VERSION 5.7 ;
  NOWIREEXTENSIONATPIN ON ;
  DIVIDERCHAR "/" ;
  BUSBITCHARS "[]" ;
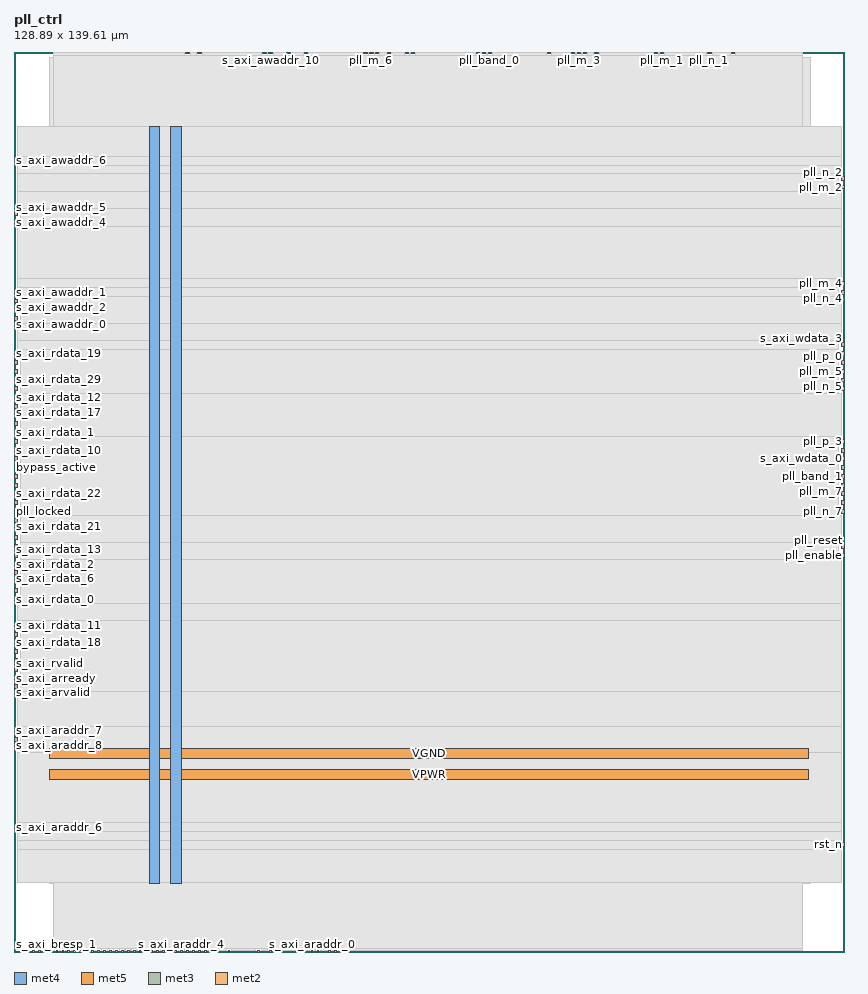
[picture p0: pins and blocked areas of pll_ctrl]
MACRO pll_ctrl
  CLASS BLOCK ;
  FOREIGN pll_ctrl ;
  ORIGIN 0.000 0.000 ;
  SIZE 128.890 BY 139.610 ;
  PIN VGND
    DIRECTION INOUT ;
    USE GROUND ;
    PORT
      LAYER met4 ;
        RECT 24.340 10.640 25.940 128.080 ;
    END
    PORT
      LAYER met5 ;
        RECT 5.520 30.030 123.280 31.630 ;
    END
  END VGND
  PIN VPWR
    DIRECTION INOUT ;
    USE POWER ;
    PORT
      LAYER met4 ;
        RECT 21.040 10.640 22.640 128.080 ;
    END
    PORT
      LAYER met5 ;
        RECT 5.520 26.730 123.280 28.330 ;
    END
  END VPWR
  PIN bypass_active
    DIRECTION OUTPUT ;
    USE SIGNAL ;
    ANTENNAGATEAREA 0.434700 ;
    ANTENNADIFFAREA 1.137600 ;
    PORT
      LAYER met3 ;
        RECT 0.000 74.840 0.600 75.440 ;
    END
  END bypass_active
  PIN pll_band_0
    DIRECTION OUTPUT ;
    USE SIGNAL ;
    ANTENNAGATEAREA 0.434700 ;
    ANTENNADIFFAREA 1.137600 ;
    PORT
      LAYER met2 ;
        RECT 73.690 139.330 73.970 139.610 ;
    END
  END pll_band_0
  PIN pll_band_1
    DIRECTION OUTPUT ;
    USE SIGNAL ;
    ANTENNAGATEAREA 0.434700 ;
    ANTENNADIFFAREA 1.137600 ;
    PORT
      LAYER met3 ;
        RECT 128.290 73.480 128.890 74.080 ;
    END
  END pll_band_1
  PIN pll_enable
    DIRECTION OUTPUT ;
    USE SIGNAL ;
    ANTENNAGATEAREA 0.434700 ;
    ANTENNADIFFAREA 1.137600 ;
    PORT
      LAYER met3 ;
        RECT 128.290 61.240 128.890 61.840 ;
    END
  END pll_enable
  PIN pll_lock_raw
    DIRECTION INPUT ;
    USE SIGNAL ;
    PORT
      LAYER met2 ;
        RECT 1.930 0.000 2.210 0.280 ;
    END
  END pll_lock_raw
  PIN pll_locked
    DIRECTION OUTPUT ;
    USE SIGNAL ;
    ANTENNAGATEAREA 0.434700 ;
    ANTENNADIFFAREA 1.137600 ;
    PORT
      LAYER met3 ;
        RECT 0.000 68.040 0.600 68.640 ;
    END
  END pll_locked
  PIN pll_m_0
    DIRECTION OUTPUT ;
    USE SIGNAL ;
    ANTENNAGATEAREA 0.434700 ;
    ANTENNADIFFAREA 1.137600 ;
    PORT
      LAYER met2 ;
        RECT 72.770 139.330 73.050 139.610 ;
    END
  END pll_m_0
  PIN pll_m_1
    DIRECTION OUTPUT ;
    USE SIGNAL ;
    ANTENNAGATEAREA 0.434700 ;
    ANTENNADIFFAREA 1.137600 ;
    PORT
      LAYER met2 ;
        RECT 100.370 139.330 100.650 139.610 ;
    END
  END pll_m_1
  PIN pll_m_2
    DIRECTION OUTPUT ;
    USE SIGNAL ;
    ANTENNAGATEAREA 0.434700 ;
    ANTENNADIFFAREA 1.137600 ;
    PORT
      LAYER met3 ;
        RECT 128.290 118.360 128.890 118.960 ;
    END
  END pll_m_2
  PIN pll_m_3
    DIRECTION OUTPUT ;
    USE SIGNAL ;
    ANTENNAGATEAREA 0.434700 ;
    ANTENNADIFFAREA 1.137600 ;
    PORT
      LAYER met2 ;
        RECT 87.490 139.330 87.770 139.610 ;
    END
  END pll_m_3
  PIN pll_m_4
    DIRECTION OUTPUT ;
    USE SIGNAL ;
    ANTENNAGATEAREA 0.434700 ;
    ANTENNADIFFAREA 1.137600 ;
    PORT
      LAYER met3 ;
        RECT 128.290 103.400 128.890 104.000 ;
    END
  END pll_m_4
  PIN pll_m_5
    DIRECTION OUTPUT ;
    USE SIGNAL ;
    ANTENNAGATEAREA 0.434700 ;
    ANTENNADIFFAREA 1.137600 ;
    PORT
      LAYER met3 ;
        RECT 128.290 89.800 128.890 90.400 ;
    END
  END pll_m_5
  PIN pll_m_6
    DIRECTION OUTPUT ;
    USE SIGNAL ;
    ANTENNAGATEAREA 0.434700 ;
    ANTENNADIFFAREA 1.137600 ;
    PORT
      LAYER met2 ;
        RECT 55.290 139.330 55.570 139.610 ;
    END
  END pll_m_6
  PIN pll_m_7
    DIRECTION OUTPUT ;
    USE SIGNAL ;
    ANTENNAGATEAREA 0.434700 ;
    ANTENNADIFFAREA 1.137600 ;
    PORT
      LAYER met3 ;
        RECT 128.290 72.120 128.890 72.720 ;
    END
  END pll_m_7
  PIN pll_n_0
    DIRECTION OUTPUT ;
    USE SIGNAL ;
    ANTENNAGATEAREA 0.434700 ;
    ANTENNADIFFAREA 1.137600 ;
    PORT
      LAYER met2 ;
        RECT 71.850 139.330 72.130 139.610 ;
    END
  END pll_n_0
  PIN pll_n_1
    DIRECTION OUTPUT ;
    USE SIGNAL ;
    ANTENNAGATEAREA 0.434700 ;
    ANTENNADIFFAREA 1.137600 ;
    PORT
      LAYER met2 ;
        RECT 107.730 139.330 108.010 139.610 ;
    END
  END pll_n_1
  PIN pll_n_2
    DIRECTION OUTPUT ;
    USE SIGNAL ;
    ANTENNAGATEAREA 0.434700 ;
    ANTENNADIFFAREA 1.137600 ;
    PORT
      LAYER met3 ;
        RECT 128.290 119.720 128.890 120.320 ;
    END
  END pll_n_2
  PIN pll_n_3
    DIRECTION OUTPUT ;
    USE SIGNAL ;
    ANTENNAGATEAREA 0.434700 ;
    ANTENNADIFFAREA 1.137600 ;
    PORT
      LAYER met2 ;
        RECT 82.890 139.330 83.170 139.610 ;
    END
  END pll_n_3
  PIN pll_n_4
    DIRECTION OUTPUT ;
    USE SIGNAL ;
    ANTENNAGATEAREA 0.434700 ;
    ANTENNADIFFAREA 1.137600 ;
    PORT
      LAYER met3 ;
        RECT 128.290 102.040 128.890 102.640 ;
    END
  END pll_n_4
  PIN pll_n_5
    DIRECTION OUTPUT ;
    USE SIGNAL ;
    ANTENNAGATEAREA 0.434700 ;
    ANTENNADIFFAREA 1.137600 ;
    PORT
      LAYER met3 ;
        RECT 128.290 88.440 128.890 89.040 ;
    END
  END pll_n_5
  PIN pll_n_6
    DIRECTION OUTPUT ;
    USE SIGNAL ;
    ANTENNAGATEAREA 0.434700 ;
    ANTENNADIFFAREA 1.137600 ;
    PORT
      LAYER met2 ;
        RECT 54.370 139.330 54.650 139.610 ;
    END
  END pll_n_6
  PIN pll_n_7
    DIRECTION OUTPUT ;
    USE SIGNAL ;
    ANTENNAGATEAREA 0.434700 ;
    ANTENNADIFFAREA 1.137600 ;
    PORT
      LAYER met3 ;
        RECT 128.290 68.040 128.890 68.640 ;
    END
  END pll_n_7
  PIN pll_p_0
    DIRECTION OUTPUT ;
    USE SIGNAL ;
    ANTENNAGATEAREA 0.434700 ;
    ANTENNADIFFAREA 1.137600 ;
    PORT
      LAYER met3 ;
        RECT 128.290 91.160 128.890 91.760 ;
    END
  END pll_p_0
  PIN pll_p_1
    DIRECTION OUTPUT ;
    USE SIGNAL ;
    ANTENNAGATEAREA 0.434700 ;
    ANTENNADIFFAREA 1.137600 ;
    PORT
      LAYER met3 ;
        RECT 128.290 87.080 128.890 87.680 ;
    END
  END pll_p_1
  PIN pll_p_2
    DIRECTION OUTPUT ;
    USE SIGNAL ;
    ANTENNAGATEAREA 0.434700 ;
    ANTENNADIFFAREA 1.137600 ;
    PORT
      LAYER met2 ;
        RECT 61.730 139.330 62.010 139.610 ;
    END
  END pll_p_2
  PIN pll_p_3
    DIRECTION OUTPUT ;
    USE SIGNAL ;
    ANTENNAGATEAREA 0.434700 ;
    ANTENNADIFFAREA 1.137600 ;
    PORT
      LAYER met3 ;
        RECT 128.290 78.920 128.890 79.520 ;
    END
  END pll_p_3
  PIN pll_reset
    DIRECTION OUTPUT ;
    USE SIGNAL ;
    ANTENNAGATEAREA 0.434700 ;
    ANTENNADIFFAREA 1.137600 ;
    PORT
      LAYER met3 ;
        RECT 128.290 62.600 128.890 63.200 ;
    END
  END pll_reset
  PIN rst_n
    DIRECTION INPUT ;
    USE SIGNAL ;
    ANTENNAGATEAREA 0.647700 ;
    ANTENNADIFFAREA 0.434700 ;
    PORT
      LAYER met3 ;
        RECT 128.290 16.360 128.890 16.960 ;
    END
  END rst_n
  PIN s_axi_araddr_0
    DIRECTION INPUT ;
    USE SIGNAL ;
    ANTENNAGATEAREA 0.647700 ;
    ANTENNADIFFAREA 0.434700 ;
    PORT
      LAYER met2 ;
        RECT 46.090 0.000 46.370 0.280 ;
    END
  END s_axi_araddr_0
  PIN s_axi_araddr_1
    DIRECTION INPUT ;
    USE SIGNAL ;
    ANTENNAGATEAREA 0.647700 ;
    ANTENNADIFFAREA 0.434700 ;
    PORT
      LAYER met2 ;
        RECT 48.850 0.000 49.130 0.280 ;
    END
  END s_axi_araddr_1
  PIN s_axi_araddr_10
    DIRECTION INPUT ;
    USE SIGNAL ;
    ANTENNAGATEAREA 0.647700 ;
    ANTENNADIFFAREA 0.434700 ;
    PORT
      LAYER met2 ;
        RECT 37.810 0.000 38.090 0.280 ;
    END
  END s_axi_araddr_10
  PIN s_axi_araddr_11
    DIRECTION INPUT ;
    USE SIGNAL ;
    ANTENNAGATEAREA 0.647700 ;
    ANTENNADIFFAREA 0.434700 ;
    PORT
      LAYER met2 ;
        RECT 47.010 0.000 47.290 0.280 ;
    END
  END s_axi_araddr_11
  PIN s_axi_araddr_2
    DIRECTION INPUT ;
    USE SIGNAL ;
    ANTENNAGATEAREA 0.647700 ;
    ANTENNADIFFAREA 0.434700 ;
    PORT
      LAYER met2 ;
        RECT 39.650 0.000 39.930 0.280 ;
    END
  END s_axi_araddr_2
  PIN s_axi_araddr_3
    DIRECTION INPUT ;
    USE SIGNAL ;
    ANTENNAGATEAREA 0.647700 ;
    ANTENNADIFFAREA 0.434700 ;
    PORT
      LAYER met2 ;
        RECT 33.210 0.000 33.490 0.280 ;
    END
  END s_axi_araddr_3
  PIN s_axi_araddr_4
    DIRECTION INPUT ;
    USE SIGNAL ;
    ANTENNAGATEAREA 0.647700 ;
    ANTENNADIFFAREA 0.434700 ;
    PORT
      LAYER met2 ;
        RECT 25.850 0.000 26.130 0.280 ;
    END
  END s_axi_araddr_4
  PIN s_axi_araddr_5
    DIRECTION INPUT ;
    USE SIGNAL ;
    ANTENNAGATEAREA 0.647700 ;
    ANTENNADIFFAREA 0.434700 ;
    PORT
      LAYER met2 ;
        RECT 18.490 0.000 18.770 0.280 ;
    END
  END s_axi_araddr_5
  PIN s_axi_araddr_6
    DIRECTION INPUT ;
    USE SIGNAL ;
    ANTENNAGATEAREA 0.647700 ;
    ANTENNADIFFAREA 0.434700 ;
    PORT
      LAYER met3 ;
        RECT 0.000 19.080 0.600 19.680 ;
    END
  END s_axi_araddr_6
  PIN s_axi_araddr_7
    DIRECTION INPUT ;
    USE SIGNAL ;
    ANTENNAGATEAREA 0.647700 ;
    ANTENNADIFFAREA 0.434700 ;
    PORT
      LAYER met3 ;
        RECT 0.000 34.040 0.600 34.640 ;
    END
  END s_axi_araddr_7
  PIN s_axi_araddr_8
    DIRECTION INPUT ;
    USE SIGNAL ;
    ANTENNAGATEAREA 0.647700 ;
    ANTENNADIFFAREA 0.434700 ;
    PORT
      LAYER met3 ;
        RECT 0.000 32.680 0.600 33.280 ;
    END
  END s_axi_araddr_8
  PIN s_axi_araddr_9
    DIRECTION INPUT ;
    USE SIGNAL ;
    ANTENNAGATEAREA 0.647700 ;
    ANTENNADIFFAREA 0.434700 ;
    PORT
      LAYER met3 ;
        RECT 0.000 31.320 0.600 31.920 ;
    END
  END s_axi_araddr_9
  PIN s_axi_arready
    DIRECTION OUTPUT ;
    USE SIGNAL ;
    ANTENNAGATEAREA 0.434700 ;
    ANTENNADIFFAREA 1.137600 ;
    PORT
      LAYER met3 ;
        RECT 0.000 42.200 0.600 42.800 ;
    END
  END s_axi_arready
  PIN s_axi_arvalid
    DIRECTION INPUT ;
    USE SIGNAL ;
    ANTENNAGATEAREA 0.647700 ;
    ANTENNADIFFAREA 0.434700 ;
    PORT
      LAYER met3 ;
        RECT 0.000 40.840 0.600 41.440 ;
    END
  END s_axi_arvalid
  PIN s_axi_awaddr_0
    DIRECTION INPUT ;
    USE SIGNAL ;
    ANTENNAGATEAREA 0.647700 ;
    ANTENNADIFFAREA 0.434700 ;
    PORT
      LAYER met3 ;
        RECT 0.000 97.960 0.600 98.560 ;
    END
  END s_axi_awaddr_0
  PIN s_axi_awaddr_1
    DIRECTION INPUT ;
    USE SIGNAL ;
    ANTENNAGATEAREA 0.647700 ;
    ANTENNADIFFAREA 0.434700 ;
    PORT
      LAYER met3 ;
        RECT 0.000 102.040 0.600 102.640 ;
    END
  END s_axi_awaddr_1
  PIN s_axi_awaddr_10
    DIRECTION INPUT ;
    USE SIGNAL ;
    ANTENNAGATEAREA 0.647700 ;
    ANTENNADIFFAREA 0.434700 ;
    PORT
      LAYER met2 ;
        RECT 39.650 139.330 39.930 139.610 ;
    END
  END s_axi_awaddr_10
  PIN s_axi_awaddr_11
    DIRECTION INPUT ;
    USE SIGNAL ;
    ANTENNAGATEAREA 0.647700 ;
    ANTENNADIFFAREA 0.434700 ;
    PORT
      LAYER met2 ;
        RECT 42.410 139.330 42.690 139.610 ;
    END
  END s_axi_awaddr_11
  PIN s_axi_awaddr_2
    DIRECTION INPUT ;
    USE SIGNAL ;
    ANTENNAGATEAREA 0.647700 ;
    ANTENNADIFFAREA 0.434700 ;
    PORT
      LAYER met3 ;
        RECT 0.000 100.680 0.600 101.280 ;
    END
  END s_axi_awaddr_2
  PIN s_axi_awaddr_3
    DIRECTION INPUT ;
    USE SIGNAL ;
    ANTENNAGATEAREA 0.647700 ;
    ANTENNADIFFAREA 0.434700 ;
    PORT
      LAYER met3 ;
        RECT 0.000 99.320 0.600 99.920 ;
    END
  END s_axi_awaddr_3
  PIN s_axi_awaddr_4
    DIRECTION INPUT ;
    USE SIGNAL ;
    ANTENNAGATEAREA 0.647700 ;
    ANTENNADIFFAREA 0.434700 ;
    PORT
      LAYER met3 ;
        RECT 0.000 112.920 0.600 113.520 ;
    END
  END s_axi_awaddr_4
  PIN s_axi_awaddr_5
    DIRECTION INPUT ;
    USE SIGNAL ;
    ANTENNAGATEAREA 0.647700 ;
    ANTENNADIFFAREA 0.434700 ;
    PORT
      LAYER met3 ;
        RECT 0.000 114.280 0.600 114.880 ;
    END
  END s_axi_awaddr_5
  PIN s_axi_awaddr_6
    DIRECTION INPUT ;
    USE SIGNAL ;
    ANTENNAGATEAREA 0.647700 ;
    ANTENNADIFFAREA 0.434700 ;
    PORT
      LAYER met3 ;
        RECT 0.000 122.440 0.600 123.040 ;
    END
  END s_axi_awaddr_6
  PIN s_axi_awaddr_7
    DIRECTION INPUT ;
    USE SIGNAL ;
    ANTENNAGATEAREA 0.647700 ;
    ANTENNADIFFAREA 0.434700 ;
    PORT
      LAYER met2 ;
        RECT 26.770 139.330 27.050 139.610 ;
    END
  END s_axi_awaddr_7
  PIN s_axi_awaddr_8
    DIRECTION INPUT ;
    USE SIGNAL ;
    ANTENNAGATEAREA 0.647700 ;
    ANTENNADIFFAREA 0.434700 ;
    PORT
      LAYER met2 ;
        RECT 28.610 139.330 28.890 139.610 ;
    END
  END s_axi_awaddr_8
  PIN s_axi_awaddr_9
    DIRECTION INPUT ;
    USE SIGNAL ;
    ANTENNAGATEAREA 0.647700 ;
    ANTENNADIFFAREA 0.434700 ;
    PORT
      LAYER met2 ;
        RECT 38.730 139.330 39.010 139.610 ;
    END
  END s_axi_awaddr_9
  PIN s_axi_awready
    DIRECTION OUTPUT ;
    USE SIGNAL ;
    ANTENNAGATEAREA 0.434700 ;
    ANTENNADIFFAREA 1.137600 ;
    PORT
      LAYER met2 ;
        RECT 45.170 139.330 45.450 139.610 ;
    END
  END s_axi_awready
  PIN s_axi_awvalid
    DIRECTION INPUT ;
    USE SIGNAL ;
    ANTENNAGATEAREA 0.647700 ;
    ANTENNADIFFAREA 0.434700 ;
    PORT
      LAYER met2 ;
        RECT 56.210 139.330 56.490 139.610 ;
    END
  END s_axi_awvalid
  PIN s_axi_bready
    DIRECTION INPUT ;
    USE SIGNAL ;
    PORT
      LAYER met2 ;
        RECT 2.850 0.000 3.130 0.280 ;
    END
  END s_axi_bready
  PIN s_axi_bresp_0
    DIRECTION OUTPUT ;
    USE SIGNAL ;
    PORT
      LAYER met2 ;
        RECT 3.770 0.000 4.050 0.280 ;
    END
  END s_axi_bresp_0
  PIN s_axi_bresp_1
    DIRECTION OUTPUT ;
    USE SIGNAL ;
    PORT
      LAYER met2 ;
        RECT 4.690 0.000 4.970 0.280 ;
    END
  END s_axi_bresp_1
  PIN s_axi_bvalid
    DIRECTION OUTPUT ;
    USE SIGNAL ;
    PORT
      LAYER met2 ;
        RECT 5.610 0.000 5.890 0.280 ;
    END
  END s_axi_bvalid
  PIN s_axi_rdata_0
    DIRECTION OUTPUT ;
    USE SIGNAL ;
    ANTENNAGATEAREA 0.434700 ;
    ANTENNADIFFAREA 1.137600 ;
    PORT
      LAYER met3 ;
        RECT 0.000 54.440 0.600 55.040 ;
    END
  END s_axi_rdata_0
  PIN s_axi_rdata_1
    DIRECTION OUTPUT ;
    USE SIGNAL ;
    ANTENNAGATEAREA 0.434700 ;
    ANTENNADIFFAREA 1.137600 ;
    PORT
      LAYER met3 ;
        RECT 0.000 80.280 0.600 80.880 ;
    END
  END s_axi_rdata_1
  PIN s_axi_rdata_10
    DIRECTION OUTPUT ;
    USE SIGNAL ;
    ANTENNAGATEAREA 0.434700 ;
    ANTENNADIFFAREA 1.137600 ;
    PORT
      LAYER met3 ;
        RECT 0.000 77.560 0.600 78.160 ;
    END
  END s_axi_rdata_10
  PIN s_axi_rdata_11
    DIRECTION OUTPUT ;
    USE SIGNAL ;
    ANTENNAGATEAREA 0.434700 ;
    ANTENNADIFFAREA 1.137600 ;
    PORT
      LAYER met3 ;
        RECT 0.000 50.360 0.600 50.960 ;
    END
  END s_axi_rdata_11
  PIN s_axi_rdata_12
    DIRECTION OUTPUT ;
    USE SIGNAL ;
    ANTENNAGATEAREA 0.434700 ;
    ANTENNADIFFAREA 1.137600 ;
    PORT
      LAYER met3 ;
        RECT 0.000 85.720 0.600 86.320 ;
    END
  END s_axi_rdata_12
  PIN s_axi_rdata_13
    DIRECTION OUTPUT ;
    USE SIGNAL ;
    ANTENNAGATEAREA 0.434700 ;
    ANTENNADIFFAREA 1.137600 ;
    PORT
      LAYER met3 ;
        RECT 0.000 61.240 0.600 61.840 ;
    END
  END s_axi_rdata_13
  PIN s_axi_rdata_14
    DIRECTION OUTPUT ;
    USE SIGNAL ;
    ANTENNAGATEAREA 0.434700 ;
    ANTENNADIFFAREA 1.137600 ;
    PORT
      LAYER met3 ;
        RECT 0.000 55.800 0.600 56.400 ;
    END
  END s_axi_rdata_14
  PIN s_axi_rdata_15
    DIRECTION OUTPUT ;
    USE SIGNAL ;
    ANTENNAGATEAREA 0.434700 ;
    ANTENNADIFFAREA 1.137600 ;
    PORT
      LAYER met3 ;
        RECT 0.000 65.320 0.600 65.920 ;
    END
  END s_axi_rdata_15
  PIN s_axi_rdata_16
    DIRECTION OUTPUT ;
    USE SIGNAL ;
    ANTENNAGATEAREA 0.434700 ;
    ANTENNADIFFAREA 1.137600 ;
    PORT
      LAYER met2 ;
        RECT 49.770 0.000 50.050 0.280 ;
    END
  END s_axi_rdata_16
  PIN s_axi_rdata_17
    DIRECTION OUTPUT ;
    USE SIGNAL ;
    ANTENNAGATEAREA 0.434700 ;
    ANTENNADIFFAREA 1.137600 ;
    PORT
      LAYER met3 ;
        RECT 0.000 84.360 0.600 84.960 ;
    END
  END s_axi_rdata_17
  PIN s_axi_rdata_18
    DIRECTION OUTPUT ;
    USE SIGNAL ;
    ANTENNAGATEAREA 0.434700 ;
    ANTENNADIFFAREA 1.137600 ;
    PORT
      LAYER met3 ;
        RECT 0.000 47.640 0.600 48.240 ;
    END
  END s_axi_rdata_18
  PIN s_axi_rdata_19
    DIRECTION OUTPUT ;
    USE SIGNAL ;
    ANTENNAGATEAREA 0.434700 ;
    ANTENNADIFFAREA 1.137600 ;
    PORT
      LAYER met3 ;
        RECT 0.000 92.520 0.600 93.120 ;
    END
  END s_axi_rdata_19
  PIN s_axi_rdata_2
    DIRECTION OUTPUT ;
    USE SIGNAL ;
    ANTENNAGATEAREA 0.434700 ;
    ANTENNADIFFAREA 1.137600 ;
    PORT
      LAYER met3 ;
        RECT 0.000 59.880 0.600 60.480 ;
    END
  END s_axi_rdata_2
  PIN s_axi_rdata_20
    DIRECTION OUTPUT ;
    USE SIGNAL ;
    ANTENNAGATEAREA 0.434700 ;
    ANTENNADIFFAREA 1.137600 ;
    PORT
      LAYER met3 ;
        RECT 0.000 76.200 0.600 76.800 ;
    END
  END s_axi_rdata_20
  PIN s_axi_rdata_21
    DIRECTION OUTPUT ;
    USE SIGNAL ;
    ANTENNAGATEAREA 0.434700 ;
    ANTENNADIFFAREA 1.137600 ;
    PORT
      LAYER met3 ;
        RECT 0.000 66.680 0.600 67.280 ;
    END
  END s_axi_rdata_21
  PIN s_axi_rdata_22
    DIRECTION OUTPUT ;
    USE SIGNAL ;
    ANTENNAGATEAREA 0.434700 ;
    ANTENNADIFFAREA 1.137600 ;
    PORT
      LAYER met3 ;
        RECT 0.000 70.760 0.600 71.360 ;
    END
  END s_axi_rdata_22
  PIN s_axi_rdata_23
    DIRECTION OUTPUT ;
    USE SIGNAL ;
    ANTENNAGATEAREA 0.434700 ;
    ANTENNADIFFAREA 1.137600 ;
    PORT
      LAYER met2 ;
        RECT 44.250 0.000 44.530 0.280 ;
    END
  END s_axi_rdata_23
  PIN s_axi_rdata_24
    DIRECTION OUTPUT ;
    USE SIGNAL ;
    ANTENNAGATEAREA 0.434700 ;
    ANTENNADIFFAREA 1.137600 ;
    PORT
      LAYER met3 ;
        RECT 0.000 63.960 0.600 64.560 ;
    END
  END s_axi_rdata_24
  PIN s_axi_rdata_25
    DIRECTION OUTPUT ;
    USE SIGNAL ;
    ANTENNAGATEAREA 0.434700 ;
    ANTENNADIFFAREA 1.137600 ;
    PORT
      LAYER met3 ;
        RECT 0.000 44.920 0.600 45.520 ;
    END
  END s_axi_rdata_25
  PIN s_axi_rdata_26
    DIRECTION OUTPUT ;
    USE SIGNAL ;
    ANTENNAGATEAREA 0.434700 ;
    ANTENNADIFFAREA 1.137600 ;
    PORT
      LAYER met3 ;
        RECT 0.000 81.640 0.600 82.240 ;
    END
  END s_axi_rdata_26
  PIN s_axi_rdata_27
    DIRECTION OUTPUT ;
    USE SIGNAL ;
    ANTENNAGATEAREA 0.434700 ;
    ANTENNADIFFAREA 1.137600 ;
    PORT
      LAYER met3 ;
        RECT 0.000 83.000 0.600 83.600 ;
    END
  END s_axi_rdata_27
  PIN s_axi_rdata_28
    DIRECTION OUTPUT ;
    USE SIGNAL ;
    ANTENNAGATEAREA 0.434700 ;
    ANTENNADIFFAREA 1.137600 ;
    PORT
      LAYER met2 ;
        RECT 50.690 0.000 50.970 0.280 ;
    END
  END s_axi_rdata_28
  PIN s_axi_rdata_29
    DIRECTION OUTPUT ;
    USE SIGNAL ;
    ANTENNAGATEAREA 0.434700 ;
    ANTENNADIFFAREA 1.137600 ;
    PORT
      LAYER met3 ;
        RECT 0.000 88.440 0.600 89.040 ;
    END
  END s_axi_rdata_29
  PIN s_axi_rdata_3
    DIRECTION OUTPUT ;
    USE SIGNAL ;
    ANTENNAGATEAREA 0.434700 ;
    ANTENNADIFFAREA 1.137600 ;
    PORT
      LAYER met3 ;
        RECT 0.000 72.120 0.600 72.720 ;
    END
  END s_axi_rdata_3
  PIN s_axi_rdata_30
    DIRECTION OUTPUT ;
    USE SIGNAL ;
    ANTENNAGATEAREA 0.434700 ;
    ANTENNADIFFAREA 1.137600 ;
    PORT
      LAYER met3 ;
        RECT 0.000 49.000 0.600 49.600 ;
    END
  END s_axi_rdata_30
  PIN s_axi_rdata_31
    DIRECTION OUTPUT ;
    USE SIGNAL ;
    ANTENNAGATEAREA 0.434700 ;
    ANTENNADIFFAREA 1.137600 ;
    PORT
      LAYER met3 ;
        RECT 0.000 62.600 0.600 63.200 ;
    END
  END s_axi_rdata_31
  PIN s_axi_rdata_4
    DIRECTION OUTPUT ;
    USE SIGNAL ;
    ANTENNAGATEAREA 0.434700 ;
    ANTENNADIFFAREA 1.137600 ;
    PORT
      LAYER met3 ;
        RECT 0.000 69.400 0.600 70.000 ;
    END
  END s_axi_rdata_4
  PIN s_axi_rdata_5
    DIRECTION OUTPUT ;
    USE SIGNAL ;
    ANTENNAGATEAREA 0.434700 ;
    ANTENNADIFFAREA 1.137600 ;
    PORT
      LAYER met3 ;
        RECT 0.000 57.160 0.600 57.760 ;
    END
  END s_axi_rdata_5
  PIN s_axi_rdata_6
    DIRECTION OUTPUT ;
    USE SIGNAL ;
    ANTENNAGATEAREA 0.434700 ;
    ANTENNADIFFAREA 1.137600 ;
    PORT
      LAYER met3 ;
        RECT 0.000 58.520 0.600 59.120 ;
    END
  END s_axi_rdata_6
  PIN s_axi_rdata_7
    DIRECTION OUTPUT ;
    USE SIGNAL ;
    ANTENNAGATEAREA 0.434700 ;
    ANTENNADIFFAREA 1.137600 ;
    PORT
      LAYER met3 ;
        RECT 0.000 91.160 0.600 91.760 ;
    END
  END s_axi_rdata_7
  PIN s_axi_rdata_8
    DIRECTION OUTPUT ;
    USE SIGNAL ;
    ANTENNAGATEAREA 0.434700 ;
    ANTENNADIFFAREA 1.137600 ;
    PORT
      LAYER met3 ;
        RECT 0.000 89.800 0.600 90.400 ;
    END
  END s_axi_rdata_8
  PIN s_axi_rdata_9
    DIRECTION OUTPUT ;
    USE SIGNAL ;
    ANTENNAGATEAREA 0.434700 ;
    ANTENNADIFFAREA 1.137600 ;
    PORT
      LAYER met3 ;
        RECT 0.000 73.480 0.600 74.080 ;
    END
  END s_axi_rdata_9
  PIN s_axi_rready
    DIRECTION INPUT ;
    USE SIGNAL ;
    ANTENNAGATEAREA 0.647700 ;
    ANTENNADIFFAREA 0.434700 ;
    PORT
      LAYER met3 ;
        RECT 0.000 46.280 0.600 46.880 ;
    END
  END s_axi_rready
  PIN s_axi_rresp_0
    DIRECTION OUTPUT ;
    USE SIGNAL ;
    ANTENNAGATEAREA 0.434700 ;
    ANTENNADIFFAREA 1.137600 ;
    PORT
      LAYER met3 ;
        RECT 0.000 87.080 0.600 87.680 ;
    END
  END s_axi_rresp_0
  PIN s_axi_rresp_1
    DIRECTION OUTPUT ;
    USE SIGNAL ;
    ANTENNAGATEAREA 0.434700 ;
    ANTENNADIFFAREA 1.137600 ;
    PORT
      LAYER met3 ;
        RECT 0.000 78.920 0.600 79.520 ;
    END
  END s_axi_rresp_1
  PIN s_axi_rvalid
    DIRECTION OUTPUT ;
    USE SIGNAL ;
    ANTENNAGATEAREA 0.434700 ;
    ANTENNADIFFAREA 1.137600 ;
    PORT
      LAYER met3 ;
        RECT 0.000 43.560 0.600 44.160 ;
    END
  END s_axi_rvalid
  PIN s_axi_wdata_0
    DIRECTION INPUT ;
    USE SIGNAL ;
    ANTENNAGATEAREA 0.647700 ;
    ANTENNADIFFAREA 0.434700 ;
    PORT
      LAYER met3 ;
        RECT 128.290 76.200 128.890 76.800 ;
    END
  END s_axi_wdata_0
  PIN s_axi_wdata_1
    DIRECTION INPUT ;
    USE SIGNAL ;
    ANTENNAGATEAREA 0.647700 ;
    ANTENNADIFFAREA 0.434700 ;
    PORT
      LAYER met2 ;
        RECT 90.250 139.330 90.530 139.610 ;
    END
  END s_axi_wdata_1
  PIN s_axi_wdata_10
    DIRECTION INPUT ;
    USE SIGNAL ;
    PORT
      LAYER met2 ;
        RECT 6.530 0.000 6.810 0.280 ;
    END
  END s_axi_wdata_10
  PIN s_axi_wdata_11
    DIRECTION INPUT ;
    USE SIGNAL ;
    PORT
      LAYER met2 ;
        RECT 7.450 0.000 7.730 0.280 ;
    END
  END s_axi_wdata_11
  PIN s_axi_wdata_12
    DIRECTION INPUT ;
    USE SIGNAL ;
    PORT
      LAYER met2 ;
        RECT 8.370 0.000 8.650 0.280 ;
    END
  END s_axi_wdata_12
  PIN s_axi_wdata_13
    DIRECTION INPUT ;
    USE SIGNAL ;
    PORT
      LAYER met2 ;
        RECT 9.290 0.000 9.570 0.280 ;
    END
  END s_axi_wdata_13
  PIN s_axi_wdata_14
    DIRECTION INPUT ;
    USE SIGNAL ;
    PORT
      LAYER met2 ;
        RECT 10.210 0.000 10.490 0.280 ;
    END
  END s_axi_wdata_14
  PIN s_axi_wdata_15
    DIRECTION INPUT ;
    USE SIGNAL ;
    PORT
      LAYER met2 ;
        RECT 11.130 0.000 11.410 0.280 ;
    END
  END s_axi_wdata_15
  PIN s_axi_wdata_16
    DIRECTION INPUT ;
    USE SIGNAL ;
    PORT
      LAYER met2 ;
        RECT 12.050 0.000 12.330 0.280 ;
    END
  END s_axi_wdata_16
  PIN s_axi_wdata_17
    DIRECTION INPUT ;
    USE SIGNAL ;
    PORT
      LAYER met2 ;
        RECT 12.970 0.000 13.250 0.280 ;
    END
  END s_axi_wdata_17
  PIN s_axi_wdata_18
    DIRECTION INPUT ;
    USE SIGNAL ;
    PORT
      LAYER met2 ;
        RECT 13.890 0.000 14.170 0.280 ;
    END
  END s_axi_wdata_18
  PIN s_axi_wdata_19
    DIRECTION INPUT ;
    USE SIGNAL ;
    PORT
      LAYER met2 ;
        RECT 14.810 0.000 15.090 0.280 ;
    END
  END s_axi_wdata_19
  PIN s_axi_wdata_2
    DIRECTION INPUT ;
    USE SIGNAL ;
    ANTENNAGATEAREA 0.647700 ;
    ANTENNADIFFAREA 0.434700 ;
    PORT
      LAYER met3 ;
        RECT 128.290 92.520 128.890 93.120 ;
    END
  END s_axi_wdata_2
  PIN s_axi_wdata_20
    DIRECTION INPUT ;
    USE SIGNAL ;
    PORT
      LAYER met2 ;
        RECT 15.730 0.000 16.010 0.280 ;
    END
  END s_axi_wdata_20
  PIN s_axi_wdata_21
    DIRECTION INPUT ;
    USE SIGNAL ;
    PORT
      LAYER met2 ;
        RECT 16.650 0.000 16.930 0.280 ;
    END
  END s_axi_wdata_21
  PIN s_axi_wdata_22
    DIRECTION INPUT ;
    USE SIGNAL ;
    PORT
      LAYER met2 ;
        RECT 17.570 0.000 17.850 0.280 ;
    END
  END s_axi_wdata_22
  PIN s_axi_wdata_23
    DIRECTION INPUT ;
    USE SIGNAL ;
    PORT
      LAYER met2 ;
        RECT 19.410 0.000 19.690 0.280 ;
    END
  END s_axi_wdata_23
  PIN s_axi_wdata_24
    DIRECTION INPUT ;
    USE SIGNAL ;
    PORT
      LAYER met2 ;
        RECT 20.330 0.000 20.610 0.280 ;
    END
  END s_axi_wdata_24
  PIN s_axi_wdata_25
    DIRECTION INPUT ;
    USE SIGNAL ;
    PORT
      LAYER met2 ;
        RECT 21.250 0.000 21.530 0.280 ;
    END
  END s_axi_wdata_25
  PIN s_axi_wdata_26
    DIRECTION INPUT ;
    USE SIGNAL ;
    PORT
      LAYER met2 ;
        RECT 22.170 0.000 22.450 0.280 ;
    END
  END s_axi_wdata_26
  PIN s_axi_wdata_27
    DIRECTION INPUT ;
    USE SIGNAL ;
    PORT
      LAYER met2 ;
        RECT 23.090 0.000 23.370 0.280 ;
    END
  END s_axi_wdata_27
  PIN s_axi_wdata_28
    DIRECTION INPUT ;
    USE SIGNAL ;
    PORT
      LAYER met2 ;
        RECT 24.010 0.000 24.290 0.280 ;
    END
  END s_axi_wdata_28
  PIN s_axi_wdata_29
    DIRECTION INPUT ;
    USE SIGNAL ;
    PORT
      LAYER met2 ;
        RECT 24.930 0.000 25.210 0.280 ;
    END
  END s_axi_wdata_29
  PIN s_axi_wdata_3
    DIRECTION INPUT ;
    USE SIGNAL ;
    ANTENNAGATEAREA 0.647700 ;
    ANTENNADIFFAREA 0.434700 ;
    PORT
      LAYER met3 ;
        RECT 128.290 93.880 128.890 94.480 ;
    END
  END s_axi_wdata_3
  PIN s_axi_wdata_30
    DIRECTION INPUT ;
    USE SIGNAL ;
    PORT
      LAYER met2 ;
        RECT 26.770 0.000 27.050 0.280 ;
    END
  END s_axi_wdata_30
  PIN s_axi_wdata_31
    DIRECTION INPUT ;
    USE SIGNAL ;
    PORT
      LAYER met2 ;
        RECT 27.690 0.000 27.970 0.280 ;
    END
  END s_axi_wdata_31
  PIN s_axi_wdata_4
    DIRECTION INPUT ;
    USE SIGNAL ;
    ANTENNAGATEAREA 0.647700 ;
    ANTENNADIFFAREA 0.434700 ;
    PORT
      LAYER met2 ;
        RECT 88.410 139.330 88.690 139.610 ;
    END
  END s_axi_wdata_4
  PIN s_axi_wdata_5
    DIRECTION INPUT ;
    USE SIGNAL ;
    ANTENNAGATEAREA 0.647700 ;
    ANTENNADIFFAREA 0.434700 ;
    PORT
      LAYER met2 ;
        RECT 111.410 139.330 111.690 139.610 ;
    END
  END s_axi_wdata_5
  PIN s_axi_wdata_6
    DIRECTION INPUT ;
    USE SIGNAL ;
    ANTENNAGATEAREA 0.647700 ;
    ANTENNADIFFAREA 0.434700 ;
    PORT
      LAYER met2 ;
        RECT 99.450 139.330 99.730 139.610 ;
    END
  END s_axi_wdata_6
  PIN s_axi_wdata_7
    DIRECTION INPUT ;
    USE SIGNAL ;
    ANTENNAGATEAREA 0.647700 ;
    ANTENNADIFFAREA 0.434700 ;
    PORT
      LAYER met2 ;
        RECT 86.570 139.330 86.850 139.610 ;
    END
  END s_axi_wdata_7
  PIN s_axi_wdata_8
    DIRECTION INPUT ;
    USE SIGNAL ;
    ANTENNAGATEAREA 0.647700 ;
    ANTENNADIFFAREA 0.434700 ;
    PORT
      LAYER met3 ;
        RECT 128.290 70.760 128.890 71.360 ;
    END
  END s_axi_wdata_8
  PIN s_axi_wdata_9
    DIRECTION INPUT ;
    USE SIGNAL ;
    ANTENNAGATEAREA 0.647700 ;
    ANTENNADIFFAREA 0.434700 ;
    PORT
      LAYER met3 ;
        RECT 128.290 74.840 128.890 75.440 ;
    END
  END s_axi_wdata_9
  PIN s_axi_wready
    DIRECTION OUTPUT ;
    USE SIGNAL ;
    ANTENNAGATEAREA 0.434700 ;
    ANTENNADIFFAREA 1.137600 ;
    PORT
      LAYER met2 ;
        RECT 60.810 139.330 61.090 139.610 ;
    END
  END s_axi_wready
  PIN s_axi_wstrb_0
    DIRECTION INPUT ;
    USE SIGNAL ;
    ANTENNAGATEAREA 0.647700 ;
    ANTENNADIFFAREA 0.434700 ;
    PORT
      LAYER met3 ;
        RECT 128.290 77.560 128.890 78.160 ;
    END
  END s_axi_wstrb_0
  PIN s_axi_wstrb_1
    DIRECTION INPUT ;
    USE SIGNAL ;
    ANTENNAGATEAREA 0.647700 ;
    ANTENNADIFFAREA 0.434700 ;
    PORT
      LAYER met3 ;
        RECT 128.290 69.400 128.890 70.000 ;
    END
  END s_axi_wstrb_1
  PIN s_axi_wstrb_2
    DIRECTION INPUT ;
    USE SIGNAL ;
    PORT
      LAYER met2 ;
        RECT 28.610 0.000 28.890 0.280 ;
    END
  END s_axi_wstrb_2
  PIN s_axi_wstrb_3
    DIRECTION INPUT ;
    USE SIGNAL ;
    PORT
      LAYER met2 ;
        RECT 29.530 0.000 29.810 0.280 ;
    END
  END s_axi_wstrb_3
  PIN s_axi_wvalid
    DIRECTION INPUT ;
    USE SIGNAL ;
    ANTENNAGATEAREA 0.647700 ;
    ANTENNADIFFAREA 0.434700 ;
    PORT
      LAYER met2 ;
        RECT 58.050 139.330 58.330 139.610 ;
    END
  END s_axi_wvalid
  PIN sys_clk
    DIRECTION OUTPUT ;
    USE SIGNAL ;
    PORT
      LAYER met2 ;
        RECT 30.450 0.000 30.730 0.280 ;
    END
  END sys_clk
  OBS
      LAYER nwell ;
        RECT 5.330 10.795 123.470 128.030 ;
      LAYER li1 ;
        RECT 5.520 10.795 123.280 127.925 ;
      LAYER met1 ;
        RECT 5.520 10.640 123.580 138.680 ;
      LAYER met2 ;
        RECT 6.070 139.050 26.490 139.540 ;
        RECT 27.330 139.050 28.330 139.540 ;
        RECT 29.170 139.050 38.450 139.540 ;
        RECT 39.290 139.050 39.370 139.540 ;
        RECT 40.210 139.050 42.130 139.540 ;
        RECT 42.970 139.050 44.890 139.540 ;
        RECT 45.730 139.050 54.090 139.540 ;
        RECT 54.930 139.050 55.010 139.540 ;
        RECT 55.850 139.050 55.930 139.540 ;
        RECT 56.770 139.050 57.770 139.540 ;
        RECT 58.610 139.050 60.530 139.540 ;
        RECT 61.370 139.050 61.450 139.540 ;
        RECT 62.290 139.050 71.570 139.540 ;
        RECT 72.410 139.050 72.490 139.540 ;
        RECT 73.330 139.050 73.410 139.540 ;
        RECT 74.250 139.050 82.610 139.540 ;
        RECT 83.450 139.050 86.290 139.540 ;
        RECT 87.130 139.050 87.210 139.540 ;
        RECT 88.050 139.050 88.130 139.540 ;
        RECT 88.970 139.050 89.970 139.540 ;
        RECT 90.810 139.050 99.170 139.540 ;
        RECT 100.010 139.050 100.090 139.540 ;
        RECT 100.930 139.050 107.450 139.540 ;
        RECT 108.290 139.050 111.130 139.540 ;
        RECT 111.970 139.050 122.270 139.540 ;
        RECT 6.070 0.560 122.270 139.050 ;
        RECT 6.170 0.280 6.250 0.560 ;
        RECT 7.090 0.280 7.170 0.560 ;
        RECT 8.010 0.280 8.090 0.560 ;
        RECT 8.930 0.280 9.010 0.560 ;
        RECT 9.850 0.280 9.930 0.560 ;
        RECT 10.770 0.280 10.850 0.560 ;
        RECT 11.690 0.280 11.770 0.560 ;
        RECT 12.610 0.280 12.690 0.560 ;
        RECT 13.530 0.280 13.610 0.560 ;
        RECT 14.450 0.280 14.530 0.560 ;
        RECT 15.370 0.280 15.450 0.560 ;
        RECT 16.290 0.280 16.370 0.560 ;
        RECT 17.210 0.280 17.290 0.560 ;
        RECT 18.130 0.280 18.210 0.560 ;
        RECT 19.050 0.280 19.130 0.560 ;
        RECT 19.970 0.280 20.050 0.560 ;
        RECT 20.890 0.280 20.970 0.560 ;
        RECT 21.810 0.280 21.890 0.560 ;
        RECT 22.730 0.280 22.810 0.560 ;
        RECT 23.650 0.280 23.730 0.560 ;
        RECT 24.570 0.280 24.650 0.560 ;
        RECT 25.490 0.280 25.570 0.560 ;
        RECT 26.410 0.280 26.490 0.560 ;
        RECT 27.330 0.280 27.410 0.560 ;
        RECT 28.250 0.280 28.330 0.560 ;
        RECT 29.170 0.280 29.250 0.560 ;
        RECT 30.090 0.280 30.170 0.560 ;
        RECT 31.010 0.280 32.930 0.560 ;
        RECT 33.770 0.280 37.530 0.560 ;
        RECT 38.370 0.280 39.370 0.560 ;
        RECT 40.210 0.280 43.970 0.560 ;
        RECT 44.810 0.280 45.810 0.560 ;
        RECT 46.650 0.280 46.730 0.560 ;
        RECT 47.570 0.280 48.570 0.560 ;
        RECT 49.410 0.280 49.490 0.560 ;
        RECT 50.330 0.280 50.410 0.560 ;
        RECT 51.250 0.280 122.270 0.560 ;
      LAYER met3 ;
        RECT 0.600 123.440 128.290 128.005 ;
        RECT 1.000 122.040 128.290 123.440 ;
        RECT 0.600 120.720 128.290 122.040 ;
        RECT 0.600 117.960 127.890 120.720 ;
        RECT 0.600 115.280 128.290 117.960 ;
        RECT 1.000 112.520 128.290 115.280 ;
        RECT 0.600 104.400 128.290 112.520 ;
        RECT 0.600 103.040 127.890 104.400 ;
        RECT 1.000 101.640 127.890 103.040 ;
        RECT 1.000 97.560 128.290 101.640 ;
        RECT 0.600 94.880 128.290 97.560 ;
        RECT 0.600 93.520 127.890 94.880 ;
        RECT 1.000 86.680 127.890 93.520 ;
        RECT 1.000 79.920 128.290 86.680 ;
        RECT 1.000 67.640 127.890 79.920 ;
        RECT 1.000 63.600 128.290 67.640 ;
        RECT 1.000 60.840 127.890 63.600 ;
        RECT 1.000 54.040 128.290 60.840 ;
        RECT 0.600 51.360 128.290 54.040 ;
        RECT 1.000 40.440 128.290 51.360 ;
        RECT 0.600 35.040 128.290 40.440 ;
        RECT 1.000 30.920 128.290 35.040 ;
        RECT 0.600 20.080 128.290 30.920 ;
        RECT 1.000 18.680 128.290 20.080 ;
        RECT 0.600 17.360 128.290 18.680 ;
        RECT 0.600 15.960 127.890 17.360 ;
        RECT 0.600 10.715 128.290 15.960 ;
  END
END pll_ctrl
END LIBRARY

